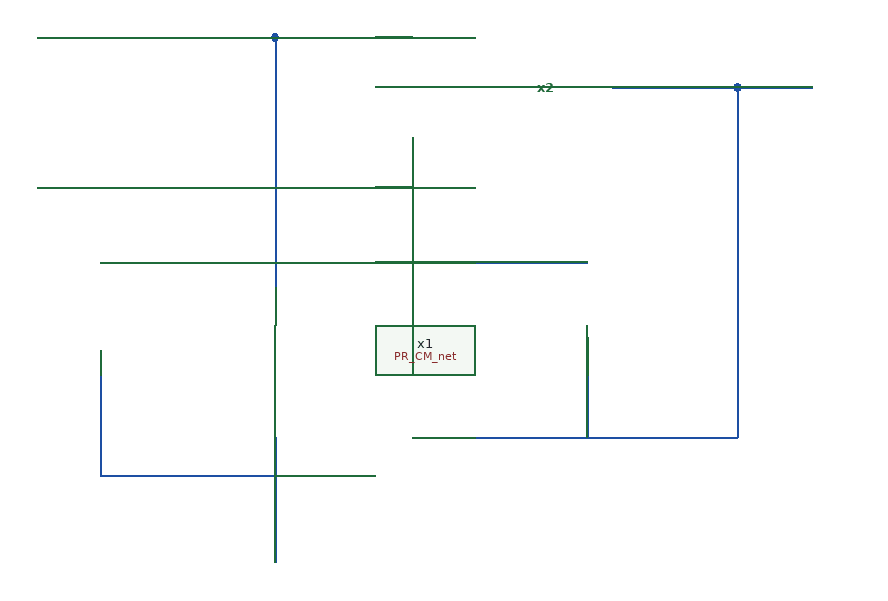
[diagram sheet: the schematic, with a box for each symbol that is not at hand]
v {xschem version=3.4.5 file_version=1.2
}
G {}
K {}
V {}
S {}
E {}
N 340 -320 340 -200 {}
N 340 -80 600 -80 {}
N 600 -360 600 -80 {}
N 500 -360 600 -360 {}
N 600 -360 660 -360 {}
N 230 -400 340 -400 {}
N 230 -400 230 -200 {}
N 230 -80 230 20 {}
N 40 -400 230 -400 {}
N 40 -280 340 -280 {}
N 340 -220 480 -220 {}
N 480 -160 480 -80 {}
N 120 -220 230 -220 {}
N 120 -50 230 -50 {}
N 90 -50 120 -50 {}
N 90 -150 90 -50 {}
N 90 -220 120 -220 {}
C {PR_CM_net.sym} 390 -70 0 0 {name=x1}
C {Folded/FoldedCascode.sym} 440 -360 0 0 {name=x2}
